VERSION 5.7 ;
  NOWIREEXTENSIONATPIN ON ;
  DIVIDERCHAR "/" ;
  BUSBITCHARS "[]" ;
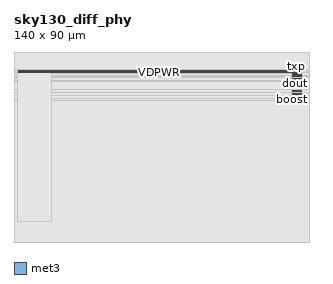
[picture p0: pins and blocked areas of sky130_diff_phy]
MACRO sky130_diff_phy
  CLASS BLOCK ;
  FOREIGN sky130_diff_phy ;
  ORIGIN 0.000 0.000 ;
  SIZE 140.000 BY 90.000 ;
  PIN din
    DIRECTION INPUT ;
    USE SIGNAL ;
    ANTENNAGATEAREA 0.900000 ;
    PORT
      LAYER met3 ;
        RECT 132.000 69.800 136.000 70.200 ;
    END
  END din
  PIN boost
    DIRECTION INPUT ;
    USE SIGNAL ;
    ANTENNAGATEAREA 2.100000 ;
    PORT
      LAYER met3 ;
        RECT 132.000 67.400 136.000 67.800 ;
    END
  END boost
  PIN rxp
    DIRECTION INPUT ;
    USE SIGNAL ;
    ANTENNAGATEAREA 24.000000 ;
    PORT
      LAYER met3 ;
        RECT 132.000 77.000 136.000 77.400 ;
    END
  END rxp
  PIN rxn
    DIRECTION INPUT ;
    USE SIGNAL ;
    ANTENNAGATEAREA 24.000000 ;
    PORT
      LAYER met3 ;
        RECT 132.000 76.200 136.000 76.600 ;
    END
  END rxn
  PIN txp
    DIRECTION OUTPUT ;
    USE SIGNAL ;
    PORT
      LAYER met3 ;
        RECT 132.000 79.400 136.000 79.800 ;
    END
  END txp
  PIN txn
    DIRECTION OUTPUT ;
    USE SIGNAL ;
    PORT
      LAYER met3 ;
        RECT 132.000 78.600 136.000 79.000 ;
    END
  END txn
  PIN dout
    DIRECTION OUTPUT ;
    USE SIGNAL ;
    ANTENNADIFFAREA 1.740000 ;
    PORT
      LAYER met3 ;
        RECT 132.000 71.400 136.000 71.800 ;
    END
  END dout
  PIN VDPWR
    DIRECTION INOUT ;
    USE POWER ;
    PORT
      LAYER met3 ;
        RECT 2.000 80.200 136.000 80.600 ;
    END
  END VDPWR
  PIN VGND
    DIRECTION INOUT ;
    USE GROUND ;
    PORT
      LAYER met3 ;
        RECT 2.000 81.000 136.000 81.400 ;
    END
  END VGND
  OBS
    LAYER met1 ;
      RECT 0.000 0.000 140.000 90.000 ;
    LAYER met2 ;
      RECT 0.000 0.000 140.000 90.000 ;
    LAYER met3 ;
      RECT 0.000 0.000 140.000 67.000 ;
      RECT 0.000 68.200 140.000 69.400 ;
      RECT 0.000 67.000 131.600 68.200 ;
      RECT 136.400 67.000 140.000 68.200 ;
      RECT 0.000 70.600 140.000 71.000 ;
      RECT 0.000 72.200 140.000 75.800 ;
      RECT 0.000 71.000 131.600 72.200 ;
      RECT 136.400 71.000 140.000 72.200 ;
      RECT 0.000 75.800 131.600 76.600 ;
      RECT 136.400 75.800 140.000 76.600 ;
      RECT 0.000 77.800 140.000 78.200 ;
      RECT 0.000 78.200 131.600 79.000 ;
      RECT 136.400 78.200 140.000 79.000 ;
      RECT 0.000 81.800 140.000 90.000 ;
      RECT 0.000 81.000 1.600 81.800 ;
      RECT 136.400 81.000 140.000 81.800 ;
      RECT 0.000 80.200 1.600 81.000 ;
      RECT 136.400 80.200 140.000 81.000 ;
      RECT 0.000 79.000 131.600 79.800 ;
      RECT 0.000 79.800 1.600 80.200 ;
      RECT 136.400 79.000 140.000 80.200 ;
      RECT 0.000 76.600 131.600 77.800 ;
      RECT 136.400 76.600 140.000 77.800 ;
      RECT 0.000 69.400 131.600 70.600 ;
      RECT 136.400 69.400 140.000 70.600 ;
    LAYER met4 ;
      RECT 1.600 9.600 17.600 81.600 ;
  END
END sky130_diff_phy
END LIBRARY

